VERSION 5.7 ;
  NOWIREEXTENSIONATPIN ON ;
  DIVIDERCHAR "/" ;
  BUSBITCHARS "[]" ;
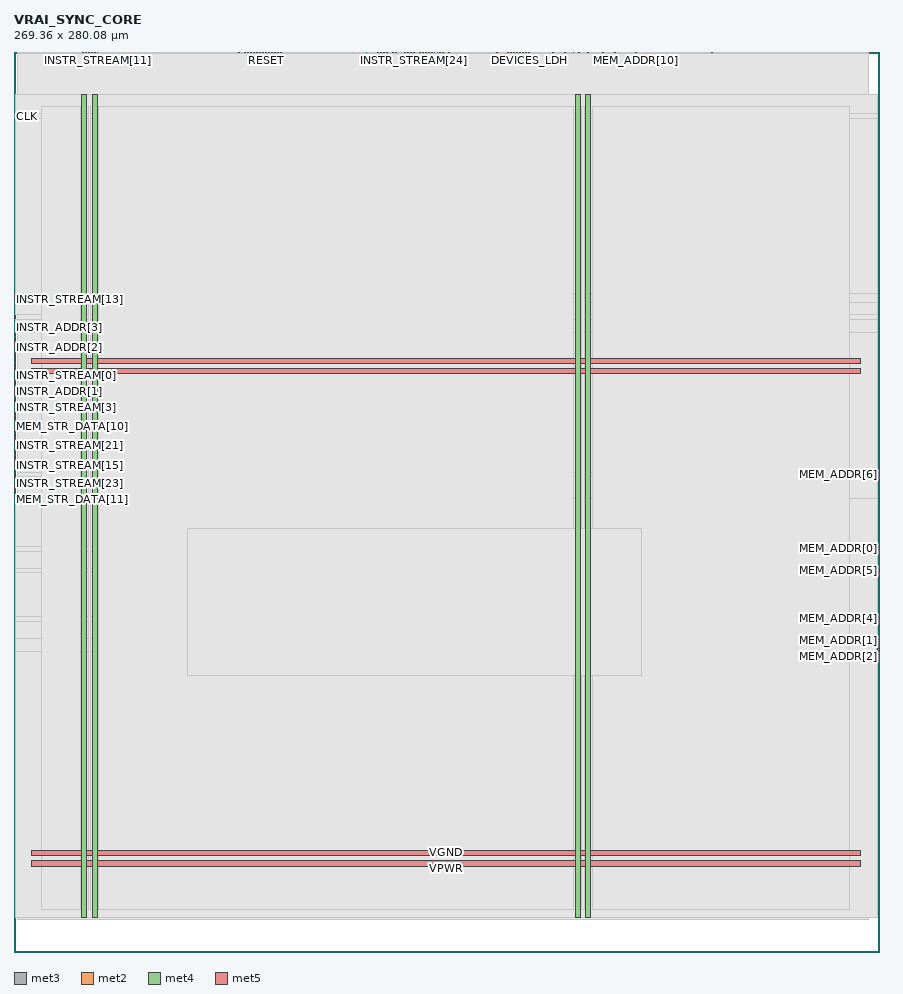
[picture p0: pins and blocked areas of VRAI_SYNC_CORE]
MACRO VRAI_SYNC_CORE
  CLASS BLOCK ;
  FOREIGN VRAI_SYNC_CORE ;
  ORIGIN 0.000 0.000 ;
  SIZE 269.360 BY 280.080 ;
  PIN CLK
    DIRECTION INPUT ;
    USE SIGNAL ;
    ANTENNAGATEAREA 0.852000 ;
    PORT
      LAYER met3 ;
        RECT 0.000 259.800 0.600 260.400 ;
    END
  END CLK
  PIN DEVICES_LDH
    DIRECTION OUTPUT ;
    USE SIGNAL ;
    ANTENNADIFFAREA 0.702900 ;
    PORT
      LAYER met2 ;
        RECT 160.170 279.800 160.450 280.080 ;
    END
  END DEVICES_LDH
  PIN DEVICES_LDW
    DIRECTION OUTPUT ;
    USE SIGNAL ;
    ANTENNADIFFAREA 0.702900 ;
    PORT
      LAYER met2 ;
        RECT 156.490 279.800 156.770 280.080 ;
    END
  END DEVICES_LDW
  PIN DEVICES_STRH
    DIRECTION OUTPUT ;
    USE SIGNAL ;
    ANTENNADIFFAREA 0.702900 ;
    PORT
      LAYER met2 ;
        RECT 158.330 279.800 158.610 280.080 ;
    END
  END DEVICES_STRH
  PIN DEVICES_STRW
    DIRECTION OUTPUT ;
    USE SIGNAL ;
    ANTENNADIFFAREA 0.702900 ;
    PORT
      LAYER met2 ;
        RECT 150.050 279.800 150.330 280.080 ;
    END
  END DEVICES_STRW
  PIN EX_HALT
    DIRECTION OUTPUT ;
    USE SIGNAL ;
    ANTENNADIFFAREA 0.702900 ;
    PORT
      LAYER met2 ;
        RECT 81.970 279.800 82.250 280.080 ;
    END
  END EX_HALT
  PIN INSTR_ADDR[0]
    DIRECTION OUTPUT ;
    USE SIGNAL ;
    ANTENNADIFFAREA 0.702900 ;
    PORT
      LAYER met3 ;
        RECT 0.000 178.200 0.600 178.800 ;
    END
  END INSTR_ADDR[0]
  PIN INSTR_ADDR[10]
    DIRECTION OUTPUT ;
    USE SIGNAL ;
    ANTENNADIFFAREA 0.702900 ;
    PORT
      LAYER met2 ;
        RECT 75.530 279.800 75.810 280.080 ;
    END
  END INSTR_ADDR[10]
  PIN INSTR_ADDR[11]
    DIRECTION OUTPUT ;
    USE SIGNAL ;
    ANTENNADIFFAREA 0.702900 ;
    PORT
      LAYER met2 ;
        RECT 77.370 279.800 77.650 280.080 ;
    END
  END INSTR_ADDR[11]
  PIN INSTR_ADDR[12]
    DIRECTION OUTPUT ;
    USE SIGNAL ;
    ANTENNADIFFAREA 0.702900 ;
    PORT
      LAYER met2 ;
        RECT 74.610 279.800 74.890 280.080 ;
    END
  END INSTR_ADDR[12]
  PIN INSTR_ADDR[13]
    DIRECTION OUTPUT ;
    USE SIGNAL ;
    ANTENNADIFFAREA 0.702900 ;
    PORT
      LAYER met2 ;
        RECT 81.050 279.800 81.330 280.080 ;
    END
  END INSTR_ADDR[13]
  PIN INSTR_ADDR[14]
    DIRECTION OUTPUT ;
    USE SIGNAL ;
    ANTENNADIFFAREA 0.702900 ;
    PORT
      LAYER met2 ;
        RECT 80.130 279.800 80.410 280.080 ;
    END
  END INSTR_ADDR[14]
  PIN INSTR_ADDR[15]
    DIRECTION OUTPUT ;
    USE SIGNAL ;
    ANTENNADIFFAREA 0.702900 ;
    PORT
      LAYER met2 ;
        RECT 79.210 279.800 79.490 280.080 ;
    END
  END INSTR_ADDR[15]
  PIN INSTR_ADDR[1]
    DIRECTION OUTPUT ;
    USE SIGNAL ;
    ANTENNADIFFAREA 0.702900 ;
    PORT
      LAYER met3 ;
        RECT 0.000 174.120 0.600 174.720 ;
    END
  END INSTR_ADDR[1]
  PIN INSTR_ADDR[2]
    DIRECTION OUTPUT ;
    USE SIGNAL ;
    ANTENNADIFFAREA 0.702900 ;
    PORT
      LAYER met3 ;
        RECT 0.000 187.720 0.600 188.320 ;
    END
  END INSTR_ADDR[2]
  PIN INSTR_ADDR[3]
    DIRECTION OUTPUT ;
    USE SIGNAL ;
    ANTENNADIFFAREA 0.702900 ;
    PORT
      LAYER met3 ;
        RECT 0.000 191.800 0.600 192.400 ;
    END
  END INSTR_ADDR[3]
  PIN INSTR_ADDR[4]
    DIRECTION OUTPUT ;
    USE SIGNAL ;
    ANTENNADIFFAREA 0.702900 ;
    PORT
      LAYER met3 ;
        RECT 0.000 189.080 0.600 189.680 ;
    END
  END INSTR_ADDR[4]
  PIN INSTR_ADDR[5]
    DIRECTION OUTPUT ;
    USE SIGNAL ;
    ANTENNADIFFAREA 0.702900 ;
    PORT
      LAYER met2 ;
        RECT 70.010 279.800 70.290 280.080 ;
    END
  END INSTR_ADDR[5]
  PIN INSTR_ADDR[6]
    DIRECTION OUTPUT ;
    USE SIGNAL ;
    ANTENNADIFFAREA 0.702900 ;
    PORT
      LAYER met2 ;
        RECT 76.450 279.800 76.730 280.080 ;
    END
  END INSTR_ADDR[6]
  PIN INSTR_ADDR[7]
    DIRECTION OUTPUT ;
    USE SIGNAL ;
    ANTENNADIFFAREA 0.702900 ;
    PORT
      LAYER met2 ;
        RECT 73.690 279.800 73.970 280.080 ;
    END
  END INSTR_ADDR[7]
  PIN INSTR_ADDR[8]
    DIRECTION OUTPUT ;
    USE SIGNAL ;
    ANTENNADIFFAREA 0.702900 ;
    PORT
      LAYER met2 ;
        RECT 72.770 279.800 73.050 280.080 ;
    END
  END INSTR_ADDR[8]
  PIN INSTR_ADDR[9]
    DIRECTION OUTPUT ;
    USE SIGNAL ;
    ANTENNADIFFAREA 0.702900 ;
    PORT
      LAYER met2 ;
        RECT 71.850 279.800 72.130 280.080 ;
    END
  END INSTR_ADDR[9]
  PIN INSTR_STREAM[0]
    DIRECTION INPUT ;
    USE SIGNAL ;
    ANTENNAGATEAREA 0.213000 ;
    PORT
      LAYER met3 ;
        RECT 0.000 176.840 0.600 177.440 ;
    END
  END INSTR_STREAM[0]
  PIN INSTR_STREAM[10]
    DIRECTION INPUT ;
    USE SIGNAL ;
    ANTENNAGATEAREA 0.213000 ;
    PORT
      LAYER met2 ;
        RECT 23.090 279.800 23.370 280.080 ;
    END
  END INSTR_STREAM[10]
  PIN INSTR_STREAM[11]
    DIRECTION INPUT ;
    USE SIGNAL ;
    ANTENNAGATEAREA 0.213000 ;
    PORT
      LAYER met2 ;
        RECT 25.850 279.800 26.130 280.080 ;
    END
  END INSTR_STREAM[11]
  PIN INSTR_STREAM[12]
    DIRECTION INPUT ;
    USE SIGNAL ;
    ANTENNAGATEAREA 0.213000 ;
    PORT
      LAYER met2 ;
        RECT 24.010 279.800 24.290 280.080 ;
    END
  END INSTR_STREAM[12]
  PIN INSTR_STREAM[13]
    DIRECTION INPUT ;
    USE SIGNAL ;
    ANTENNAGATEAREA 0.213000 ;
    PORT
      LAYER met3 ;
        RECT 0.000 202.680 0.600 203.280 ;
    END
  END INSTR_STREAM[13]
  PIN INSTR_STREAM[14]
    DIRECTION INPUT ;
    USE SIGNAL ;
    ANTENNAGATEAREA 0.213000 ;
    PORT
      LAYER met3 ;
        RECT 0.000 141.480 0.600 142.080 ;
    END
  END INSTR_STREAM[14]
  PIN INSTR_STREAM[15]
    DIRECTION INPUT ;
    USE SIGNAL ;
    ANTENNAGATEAREA 0.213000 ;
    PORT
      LAYER met3 ;
        RECT 0.000 151.000 0.600 151.600 ;
    END
  END INSTR_STREAM[15]
  PIN INSTR_STREAM[16]
    DIRECTION INPUT ;
    USE SIGNAL ;
    ANTENNAGATEAREA 0.213000 ;
    PORT
      LAYER met3 ;
        RECT 0.000 182.280 0.600 182.880 ;
    END
  END INSTR_STREAM[16]
  PIN INSTR_STREAM[17]
    DIRECTION INPUT ;
    USE SIGNAL ;
    ANTENNAGATEAREA 0.213000 ;
    PORT
      LAYER met3 ;
        RECT 0.000 172.760 0.600 173.360 ;
    END
  END INSTR_STREAM[17]
  PIN INSTR_STREAM[18]
    DIRECTION INPUT ;
    USE SIGNAL ;
    ANTENNAGATEAREA 0.213000 ;
    PORT
      LAYER met3 ;
        RECT 0.000 190.440 0.600 191.040 ;
    END
  END INSTR_STREAM[18]
  PIN INSTR_STREAM[19]
    DIRECTION INPUT ;
    USE SIGNAL ;
    ANTENNAGATEAREA 0.213000 ;
    PORT
      LAYER met3 ;
        RECT 0.000 186.360 0.600 186.960 ;
    END
  END INSTR_STREAM[19]
  PIN INSTR_STREAM[1]
    DIRECTION INPUT ;
    USE SIGNAL ;
    ANTENNAGATEAREA 0.213000 ;
    PORT
      LAYER met3 ;
        RECT 0.000 183.640 0.600 184.240 ;
    END
  END INSTR_STREAM[1]
  PIN INSTR_STREAM[20]
    DIRECTION INPUT ;
    USE SIGNAL ;
    ANTENNAGATEAREA 0.213000 ;
    PORT
      LAYER met3 ;
        RECT 0.000 146.920 0.600 147.520 ;
    END
  END INSTR_STREAM[20]
  PIN INSTR_STREAM[21]
    DIRECTION INPUT ;
    USE SIGNAL ;
    ANTENNAGATEAREA 0.213000 ;
    PORT
      LAYER met3 ;
        RECT 0.000 155.080 0.600 155.680 ;
    END
  END INSTR_STREAM[21]
  PIN INSTR_STREAM[22]
    DIRECTION INPUT ;
    USE SIGNAL ;
    ANTENNAGATEAREA 0.213000 ;
    PORT
      LAYER met3 ;
        RECT 0.000 156.440 0.600 157.040 ;
    END
  END INSTR_STREAM[22]
  PIN INSTR_STREAM[23]
    DIRECTION INPUT ;
    USE SIGNAL ;
    ANTENNAGATEAREA 0.213000 ;
    PORT
      LAYER met3 ;
        RECT 0.000 145.560 0.600 146.160 ;
    END
  END INSTR_STREAM[23]
  PIN INSTR_STREAM[24]
    DIRECTION INPUT ;
    USE SIGNAL ;
    ANTENNAGATEAREA 0.213000 ;
    PORT
      LAYER met2 ;
        RECT 124.290 279.800 124.570 280.080 ;
    END
  END INSTR_STREAM[24]
  PIN INSTR_STREAM[25]
    DIRECTION INPUT ;
    USE SIGNAL ;
    ANTENNAGATEAREA 0.213000 ;
    PORT
      LAYER met2 ;
        RECT 121.530 279.800 121.810 280.080 ;
    END
  END INSTR_STREAM[25]
  PIN INSTR_STREAM[26]
    DIRECTION INPUT ;
    USE SIGNAL ;
    ANTENNAGATEAREA 0.213000 ;
    PORT
      LAYER met2 ;
        RECT 122.450 279.800 122.730 280.080 ;
    END
  END INSTR_STREAM[26]
  PIN INSTR_STREAM[27]
    DIRECTION INPUT ;
    USE SIGNAL ;
    ANTENNAGATEAREA 0.213000 ;
    PORT
      LAYER met2 ;
        RECT 123.370 279.800 123.650 280.080 ;
    END
  END INSTR_STREAM[27]
  PIN INSTR_STREAM[28]
    DIRECTION INPUT ;
    USE SIGNAL ;
    ANTENNAGATEAREA 0.213000 ;
    PORT
      LAYER met2 ;
        RECT 82.890 279.800 83.170 280.080 ;
    END
  END INSTR_STREAM[28]
  PIN INSTR_STREAM[29]
    DIRECTION INPUT ;
    USE SIGNAL ;
    ANTENNAGATEAREA 0.213000 ;
    PORT
      LAYER met2 ;
        RECT 117.850 279.800 118.130 280.080 ;
    END
  END INSTR_STREAM[29]
  PIN INSTR_STREAM[2]
    DIRECTION INPUT ;
    USE SIGNAL ;
    ANTENNAGATEAREA 0.213000 ;
    PORT
      LAYER met3 ;
        RECT 0.000 185.000 0.600 185.600 ;
    END
  END INSTR_STREAM[2]
  PIN INSTR_STREAM[30]
    DIRECTION INPUT ;
    USE SIGNAL ;
    ANTENNAGATEAREA 0.213000 ;
    PORT
      LAYER met2 ;
        RECT 116.010 279.800 116.290 280.080 ;
    END
  END INSTR_STREAM[30]
  PIN INSTR_STREAM[31]
    DIRECTION INPUT ;
    USE SIGNAL ;
    ANTENNAGATEAREA 0.213000 ;
    PORT
      LAYER met2 ;
        RECT 109.570 279.800 109.850 280.080 ;
    END
  END INSTR_STREAM[31]
  PIN INSTR_STREAM[3]
    DIRECTION INPUT ;
    USE SIGNAL ;
    ANTENNAGATEAREA 0.213000 ;
    PORT
      LAYER met3 ;
        RECT 0.000 171.400 0.600 172.000 ;
    END
  END INSTR_STREAM[3]
  PIN INSTR_STREAM[4]
    DIRECTION INPUT ;
    USE SIGNAL ;
    ANTENNAGATEAREA 0.213000 ;
    PORT
      LAYER met3 ;
        RECT 0.000 170.040 0.600 170.640 ;
    END
  END INSTR_STREAM[4]
  PIN INSTR_STREAM[5]
    DIRECTION INPUT ;
    USE SIGNAL ;
    ANTENNAGATEAREA 0.213000 ;
    PORT
      LAYER met3 ;
        RECT 0.000 197.240 0.600 197.840 ;
    END
  END INSTR_STREAM[5]
  PIN INSTR_STREAM[6]
    DIRECTION INPUT ;
    USE SIGNAL ;
    ANTENNAGATEAREA 0.213000 ;
    PORT
      LAYER met3 ;
        RECT 0.000 204.040 0.600 204.640 ;
    END
  END INSTR_STREAM[6]
  PIN INSTR_STREAM[7]
    DIRECTION INPUT ;
    USE SIGNAL ;
    ANTENNAGATEAREA 0.213000 ;
    PORT
      LAYER met2 ;
        RECT 24.930 279.800 25.210 280.080 ;
    END
  END INSTR_STREAM[7]
  PIN INSTR_STREAM[8]
    DIRECTION INPUT ;
    USE SIGNAL ;
    ANTENNAGATEAREA 0.213000 ;
    PORT
      LAYER met2 ;
        RECT 21.250 279.800 21.530 280.080 ;
    END
  END INSTR_STREAM[8]
  PIN INSTR_STREAM[9]
    DIRECTION INPUT ;
    USE SIGNAL ;
    ANTENNAGATEAREA 0.213000 ;
    PORT
      LAYER met2 ;
        RECT 22.170 279.800 22.450 280.080 ;
    END
  END INSTR_STREAM[9]
  PIN INVALID_MEM
    DIRECTION OUTPUT ;
    USE SIGNAL ;
    ANTENNADIFFAREA 0.702900 ;
    PORT
      LAYER met2 ;
        RECT 171.210 279.800 171.490 280.080 ;
    END
  END INVALID_MEM
  PIN MAIN_LDH
    DIRECTION OUTPUT ;
    USE SIGNAL ;
    ANTENNADIFFAREA 0.702900 ;
    PORT
      LAYER met2 ;
        RECT 159.250 279.800 159.530 280.080 ;
    END
  END MAIN_LDH
  PIN MAIN_LDW
    DIRECTION OUTPUT ;
    USE SIGNAL ;
    ANTENNADIFFAREA 0.702900 ;
    PORT
      LAYER met2 ;
        RECT 155.570 279.800 155.850 280.080 ;
    END
  END MAIN_LDW
  PIN MAIN_STRH
    DIRECTION OUTPUT ;
    USE SIGNAL ;
    ANTENNADIFFAREA 0.702900 ;
    PORT
      LAYER met2 ;
        RECT 157.410 279.800 157.690 280.080 ;
    END
  END MAIN_STRH
  PIN MAIN_STRW
    DIRECTION OUTPUT ;
    USE SIGNAL ;
    ANTENNADIFFAREA 0.702900 ;
    PORT
      LAYER met2 ;
        RECT 154.650 279.800 154.930 280.080 ;
    END
  END MAIN_STRW
  PIN MEM_ADDR[0]
    DIRECTION OUTPUT ;
    USE SIGNAL ;
    ANTENNADIFFAREA 0.702900 ;
    PORT
      LAYER met3 ;
        RECT 268.760 125.160 269.360 125.760 ;
    END
  END MEM_ADDR[0]
  PIN MEM_ADDR[10]
    DIRECTION OUTPUT ;
    USE SIGNAL ;
    ANTENNADIFFAREA 0.702900 ;
    PORT
      LAYER met2 ;
        RECT 193.290 279.800 193.570 280.080 ;
    END
  END MEM_ADDR[10]
  PIN MEM_ADDR[11]
    DIRECTION OUTPUT ;
    USE SIGNAL ;
    ANTENNADIFFAREA 0.702900 ;
    PORT
      LAYER met2 ;
        RECT 183.170 279.800 183.450 280.080 ;
    END
  END MEM_ADDR[11]
  PIN MEM_ADDR[12]
    DIRECTION OUTPUT ;
    USE SIGNAL ;
    ANTENNADIFFAREA 0.702900 ;
    PORT
      LAYER met2 ;
        RECT 178.570 279.800 178.850 280.080 ;
    END
  END MEM_ADDR[12]
  PIN MEM_ADDR[13]
    DIRECTION OUTPUT ;
    USE SIGNAL ;
    ANTENNADIFFAREA 0.702900 ;
    PORT
      LAYER met2 ;
        RECT 175.810 279.800 176.090 280.080 ;
    END
  END MEM_ADDR[13]
  PIN MEM_ADDR[14]
    DIRECTION OUTPUT ;
    USE SIGNAL ;
    ANTENNADIFFAREA 0.702900 ;
    PORT
      LAYER met2 ;
        RECT 167.530 279.800 167.810 280.080 ;
    END
  END MEM_ADDR[14]
  PIN MEM_ADDR[15]
    DIRECTION OUTPUT ;
    USE SIGNAL ;
    ANTENNADIFFAREA 0.702900 ;
    PORT
      LAYER met2 ;
        RECT 153.730 279.800 154.010 280.080 ;
    END
  END MEM_ADDR[15]
  PIN MEM_ADDR[1]
    DIRECTION OUTPUT ;
    USE SIGNAL ;
    ANTENNADIFFAREA 0.702900 ;
    PORT
      LAYER met3 ;
        RECT 268.760 96.600 269.360 97.200 ;
    END
  END MEM_ADDR[1]
  PIN MEM_ADDR[2]
    DIRECTION OUTPUT ;
    USE SIGNAL ;
    ANTENNADIFFAREA 0.702900 ;
    PORT
      LAYER met3 ;
        RECT 268.760 93.880 269.360 94.480 ;
    END
  END MEM_ADDR[2]
  PIN MEM_ADDR[3]
    DIRECTION OUTPUT ;
    USE SIGNAL ;
    ANTENNADIFFAREA 0.702900 ;
    PORT
      LAYER met3 ;
        RECT 268.760 95.240 269.360 95.840 ;
    END
  END MEM_ADDR[3]
  PIN MEM_ADDR[4]
    DIRECTION OUTPUT ;
    USE SIGNAL ;
    ANTENNADIFFAREA 0.702900 ;
    PORT
      LAYER met3 ;
        RECT 268.760 103.400 269.360 104.000 ;
    END
  END MEM_ADDR[4]
  PIN MEM_ADDR[5]
    DIRECTION OUTPUT ;
    USE SIGNAL ;
    ANTENNADIFFAREA 0.702900 ;
    PORT
      LAYER met3 ;
        RECT 268.760 118.360 269.360 118.960 ;
    END
  END MEM_ADDR[5]
  PIN MEM_ADDR[6]
    DIRECTION OUTPUT ;
    USE SIGNAL ;
    ANTENNADIFFAREA 0.702900 ;
    PORT
      LAYER met3 ;
        RECT 268.760 148.280 269.360 148.880 ;
    END
  END MEM_ADDR[6]
  PIN MEM_ADDR[7]
    DIRECTION OUTPUT ;
    USE SIGNAL ;
    ANTENNADIFFAREA 0.702900 ;
    PORT
      LAYER met2 ;
        RECT 173.970 279.800 174.250 280.080 ;
    END
  END MEM_ADDR[7]
  PIN MEM_ADDR[8]
    DIRECTION OUTPUT ;
    USE SIGNAL ;
    ANTENNADIFFAREA 0.702900 ;
    PORT
      LAYER met2 ;
        RECT 186.850 279.800 187.130 280.080 ;
    END
  END MEM_ADDR[8]
  PIN MEM_ADDR[9]
    DIRECTION OUTPUT ;
    USE SIGNAL ;
    ANTENNADIFFAREA 0.702900 ;
    PORT
      LAYER met2 ;
        RECT 217.210 279.800 217.490 280.080 ;
    END
  END MEM_ADDR[9]
  PIN MEM_LD_DATA[0]
    DIRECTION INPUT ;
    USE SIGNAL ;
    ANTENNAGATEAREA 0.213000 ;
    PORT
      LAYER met2 ;
        RECT 128.890 279.800 129.170 280.080 ;
    END
  END MEM_LD_DATA[0]
  PIN MEM_LD_DATA[10]
    DIRECTION INPUT ;
    USE SIGNAL ;
    ANTENNAGATEAREA 0.213000 ;
    PORT
      LAYER met2 ;
        RECT 132.570 279.800 132.850 280.080 ;
    END
  END MEM_LD_DATA[10]
  PIN MEM_LD_DATA[11]
    DIRECTION INPUT ;
    USE SIGNAL ;
    ANTENNAGATEAREA 0.213000 ;
    PORT
      LAYER met2 ;
        RECT 118.770 279.800 119.050 280.080 ;
    END
  END MEM_LD_DATA[11]
  PIN MEM_LD_DATA[12]
    DIRECTION INPUT ;
    USE SIGNAL ;
    ANTENNAGATEAREA 0.213000 ;
    PORT
      LAYER met2 ;
        RECT 135.330 279.800 135.610 280.080 ;
    END
  END MEM_LD_DATA[12]
  PIN MEM_LD_DATA[13]
    DIRECTION INPUT ;
    USE SIGNAL ;
    ANTENNAGATEAREA 0.213000 ;
    PORT
      LAYER met2 ;
        RECT 130.730 279.800 131.010 280.080 ;
    END
  END MEM_LD_DATA[13]
  PIN MEM_LD_DATA[14]
    DIRECTION INPUT ;
    USE SIGNAL ;
    ANTENNAGATEAREA 0.213000 ;
    PORT
      LAYER met2 ;
        RECT 131.650 279.800 131.930 280.080 ;
    END
  END MEM_LD_DATA[14]
  PIN MEM_LD_DATA[15]
    DIRECTION INPUT ;
    USE SIGNAL ;
    ANTENNAGATEAREA 0.213000 ;
    PORT
      LAYER met2 ;
        RECT 127.050 279.800 127.330 280.080 ;
    END
  END MEM_LD_DATA[15]
  PIN MEM_LD_DATA[1]
    DIRECTION INPUT ;
    USE SIGNAL ;
    ANTENNAGATEAREA 0.213000 ;
    PORT
      LAYER met2 ;
        RECT 129.810 279.800 130.090 280.080 ;
    END
  END MEM_LD_DATA[1]
  PIN MEM_LD_DATA[2]
    DIRECTION INPUT ;
    USE SIGNAL ;
    ANTENNAGATEAREA 0.213000 ;
    PORT
      LAYER met2 ;
        RECT 115.090 279.800 115.370 280.080 ;
    END
  END MEM_LD_DATA[2]
  PIN MEM_LD_DATA[3]
    DIRECTION INPUT ;
    USE SIGNAL ;
    ANTENNAGATEAREA 0.213000 ;
    PORT
      LAYER met2 ;
        RECT 127.970 279.800 128.250 280.080 ;
    END
  END MEM_LD_DATA[3]
  PIN MEM_LD_DATA[4]
    DIRECTION INPUT ;
    USE SIGNAL ;
    ANTENNAGATEAREA 0.213000 ;
    PORT
      LAYER met2 ;
        RECT 113.250 279.800 113.530 280.080 ;
    END
  END MEM_LD_DATA[4]
  PIN MEM_LD_DATA[5]
    DIRECTION INPUT ;
    USE SIGNAL ;
    ANTENNAGATEAREA 0.213000 ;
    PORT
      LAYER met3 ;
        RECT 0.000 180.920 0.600 181.520 ;
    END
  END MEM_LD_DATA[5]
  PIN MEM_LD_DATA[6]
    DIRECTION INPUT ;
    USE SIGNAL ;
    ANTENNAGATEAREA 0.213000 ;
    PORT
      LAYER met3 ;
        RECT 0.000 175.480 0.600 176.080 ;
    END
  END MEM_LD_DATA[6]
  PIN MEM_LD_DATA[7]
    DIRECTION INPUT ;
    USE SIGNAL ;
    ANTENNAGATEAREA 0.213000 ;
    PORT
      LAYER met2 ;
        RECT 114.170 279.800 114.450 280.080 ;
    END
  END MEM_LD_DATA[7]
  PIN MEM_LD_DATA[8]
    DIRECTION INPUT ;
    USE SIGNAL ;
    ANTENNAGATEAREA 0.213000 ;
    PORT
      LAYER met2 ;
        RECT 133.490 279.800 133.770 280.080 ;
    END
  END MEM_LD_DATA[8]
  PIN MEM_LD_DATA[9]
    DIRECTION INPUT ;
    USE SIGNAL ;
    ANTENNAGATEAREA 0.213000 ;
    PORT
      LAYER met2 ;
        RECT 126.130 279.800 126.410 280.080 ;
    END
  END MEM_LD_DATA[9]
  PIN MEM_STR_DATA[0]
    DIRECTION OUTPUT ;
    USE SIGNAL ;
    ANTENNADIFFAREA 0.702900 ;
    PORT
      LAYER met3 ;
        RECT 0.000 153.720 0.600 154.320 ;
    END
  END MEM_STR_DATA[0]
  PIN MEM_STR_DATA[10]
    DIRECTION OUTPUT ;
    USE SIGNAL ;
    ANTENNADIFFAREA 0.702900 ;
    PORT
      LAYER met3 ;
        RECT 0.000 163.240 0.600 163.840 ;
    END
  END MEM_STR_DATA[10]
  PIN MEM_STR_DATA[11]
    DIRECTION OUTPUT ;
    USE SIGNAL ;
    ANTENNADIFFAREA 0.702900 ;
    PORT
      LAYER met3 ;
        RECT 0.000 142.840 0.600 143.440 ;
    END
  END MEM_STR_DATA[11]
  PIN MEM_STR_DATA[12]
    DIRECTION OUTPUT ;
    USE SIGNAL ;
    ANTENNADIFFAREA 0.702900 ;
    PORT
      LAYER met3 ;
        RECT 0.000 157.800 0.600 158.400 ;
    END
  END MEM_STR_DATA[12]
  PIN MEM_STR_DATA[13]
    DIRECTION OUTPUT ;
    USE SIGNAL ;
    ANTENNADIFFAREA 0.702900 ;
    PORT
      LAYER met3 ;
        RECT 0.000 161.880 0.600 162.480 ;
    END
  END MEM_STR_DATA[13]
  PIN MEM_STR_DATA[14]
    DIRECTION OUTPUT ;
    USE SIGNAL ;
    ANTENNADIFFAREA 0.702900 ;
    PORT
      LAYER met3 ;
        RECT 0.000 159.160 0.600 159.760 ;
    END
  END MEM_STR_DATA[14]
  PIN MEM_STR_DATA[15]
    DIRECTION OUTPUT ;
    USE SIGNAL ;
    ANTENNADIFFAREA 0.702900 ;
    PORT
      LAYER met3 ;
        RECT 0.000 144.200 0.600 144.800 ;
    END
  END MEM_STR_DATA[15]
  PIN MEM_STR_DATA[1]
    DIRECTION OUTPUT ;
    USE SIGNAL ;
    ANTENNADIFFAREA 0.702900 ;
    PORT
      LAYER met3 ;
        RECT 0.000 148.280 0.600 148.880 ;
    END
  END MEM_STR_DATA[1]
  PIN MEM_STR_DATA[2]
    DIRECTION OUTPUT ;
    USE SIGNAL ;
    ANTENNADIFFAREA 0.702900 ;
    PORT
      LAYER met3 ;
        RECT 0.000 152.360 0.600 152.960 ;
    END
  END MEM_STR_DATA[2]
  PIN MEM_STR_DATA[3]
    DIRECTION OUTPUT ;
    USE SIGNAL ;
    ANTENNADIFFAREA 0.702900 ;
    PORT
      LAYER met3 ;
        RECT 0.000 165.960 0.600 166.560 ;
    END
  END MEM_STR_DATA[3]
  PIN MEM_STR_DATA[4]
    DIRECTION OUTPUT ;
    USE SIGNAL ;
    ANTENNADIFFAREA 0.702900 ;
    PORT
      LAYER met3 ;
        RECT 0.000 167.320 0.600 167.920 ;
    END
  END MEM_STR_DATA[4]
  PIN MEM_STR_DATA[5]
    DIRECTION OUTPUT ;
    USE SIGNAL ;
    ANTENNADIFFAREA 0.702900 ;
    PORT
      LAYER met3 ;
        RECT 0.000 164.600 0.600 165.200 ;
    END
  END MEM_STR_DATA[5]
  PIN MEM_STR_DATA[6]
    DIRECTION OUTPUT ;
    USE SIGNAL ;
    ANTENNADIFFAREA 0.702900 ;
    PORT
      LAYER met3 ;
        RECT 0.000 160.520 0.600 161.120 ;
    END
  END MEM_STR_DATA[6]
  PIN MEM_STR_DATA[7]
    DIRECTION OUTPUT ;
    USE SIGNAL ;
    ANTENNADIFFAREA 0.702900 ;
    PORT
      LAYER met3 ;
        RECT 0.000 168.680 0.600 169.280 ;
    END
  END MEM_STR_DATA[7]
  PIN MEM_STR_DATA[8]
    DIRECTION OUTPUT ;
    USE SIGNAL ;
    ANTENNADIFFAREA 0.702900 ;
    PORT
      LAYER met3 ;
        RECT 0.000 149.640 0.600 150.240 ;
    END
  END MEM_STR_DATA[8]
  PIN MEM_STR_DATA[9]
    DIRECTION OUTPUT ;
    USE SIGNAL ;
    ANTENNADIFFAREA 0.702900 ;
    PORT
      LAYER met3 ;
        RECT 0.000 179.560 0.600 180.160 ;
    END
  END MEM_STR_DATA[9]
  PIN RESET
    DIRECTION INPUT ;
    USE SIGNAL ;
    ANTENNAGATEAREA 0.247500 ;
    PORT
      LAYER met2 ;
        RECT 78.290 279.800 78.570 280.080 ;
    END
  END RESET
  PIN VGND
    DIRECTION INOUT ;
    USE GROUND ;
    PORT
      LAYER met4 ;
        RECT 24.340 10.640 25.940 266.800 ;
    END
    PORT
      LAYER met4 ;
        RECT 177.940 10.640 179.540 266.800 ;
    END
    PORT
      LAYER met5 ;
        RECT 5.520 30.030 263.580 31.630 ;
    END
    PORT
      LAYER met5 ;
        RECT 5.520 183.210 263.580 184.810 ;
    END
  END VGND
  PIN VPWR
    DIRECTION INOUT ;
    USE POWER ;
    PORT
      LAYER met4 ;
        RECT 21.040 10.640 22.640 266.800 ;
    END
    PORT
      LAYER met4 ;
        RECT 174.640 10.640 176.240 266.800 ;
    END
    PORT
      LAYER met5 ;
        RECT 5.520 26.730 263.580 28.330 ;
    END
    PORT
      LAYER met5 ;
        RECT 5.520 179.910 263.580 181.510 ;
    END
  END VPWR
  OBS
      LAYER nwell ;
        RECT 5.330 10.795 263.770 266.645 ;
      LAYER li1 ;
        RECT 5.520 10.795 263.580 266.645 ;
      LAYER met1 ;
        RECT 0.990 10.240 265.810 267.200 ;
      LAYER met2 ;
        RECT 1.010 279.520 20.970 279.800 ;
        RECT 21.810 279.520 21.890 279.800 ;
        RECT 22.730 279.520 22.810 279.800 ;
        RECT 23.650 279.520 23.730 279.800 ;
        RECT 24.570 279.520 24.650 279.800 ;
        RECT 25.490 279.520 25.570 279.800 ;
        RECT 26.410 279.520 69.730 279.800 ;
        RECT 70.570 279.520 71.570 279.800 ;
        RECT 72.410 279.520 72.490 279.800 ;
        RECT 73.330 279.520 73.410 279.800 ;
        RECT 74.250 279.520 74.330 279.800 ;
        RECT 75.170 279.520 75.250 279.800 ;
        RECT 76.090 279.520 76.170 279.800 ;
        RECT 77.010 279.520 77.090 279.800 ;
        RECT 77.930 279.520 78.010 279.800 ;
        RECT 78.850 279.520 78.930 279.800 ;
        RECT 79.770 279.520 79.850 279.800 ;
        RECT 80.690 279.520 80.770 279.800 ;
        RECT 81.610 279.520 81.690 279.800 ;
        RECT 82.530 279.520 82.610 279.800 ;
        RECT 83.450 279.520 109.290 279.800 ;
        RECT 110.130 279.520 112.970 279.800 ;
        RECT 113.810 279.520 113.890 279.800 ;
        RECT 114.730 279.520 114.810 279.800 ;
        RECT 115.650 279.520 115.730 279.800 ;
        RECT 116.570 279.520 117.570 279.800 ;
        RECT 118.410 279.520 118.490 279.800 ;
        RECT 119.330 279.520 121.250 279.800 ;
        RECT 122.090 279.520 122.170 279.800 ;
        RECT 123.010 279.520 123.090 279.800 ;
        RECT 123.930 279.520 124.010 279.800 ;
        RECT 124.850 279.520 125.850 279.800 ;
        RECT 126.690 279.520 126.770 279.800 ;
        RECT 127.610 279.520 127.690 279.800 ;
        RECT 128.530 279.520 128.610 279.800 ;
        RECT 129.450 279.520 129.530 279.800 ;
        RECT 130.370 279.520 130.450 279.800 ;
        RECT 131.290 279.520 131.370 279.800 ;
        RECT 132.210 279.520 132.290 279.800 ;
        RECT 133.130 279.520 133.210 279.800 ;
        RECT 134.050 279.520 135.050 279.800 ;
        RECT 135.890 279.520 149.770 279.800 ;
        RECT 150.610 279.520 153.450 279.800 ;
        RECT 154.290 279.520 154.370 279.800 ;
        RECT 155.210 279.520 155.290 279.800 ;
        RECT 156.130 279.520 156.210 279.800 ;
        RECT 157.050 279.520 157.130 279.800 ;
        RECT 157.970 279.520 158.050 279.800 ;
        RECT 158.890 279.520 158.970 279.800 ;
        RECT 159.810 279.520 159.890 279.800 ;
        RECT 160.730 279.520 167.250 279.800 ;
        RECT 168.090 279.520 170.930 279.800 ;
        RECT 171.770 279.520 173.690 279.800 ;
        RECT 174.530 279.520 175.530 279.800 ;
        RECT 176.370 279.520 178.290 279.800 ;
        RECT 179.130 279.520 182.890 279.800 ;
        RECT 183.730 279.520 186.570 279.800 ;
        RECT 187.410 279.520 193.010 279.800 ;
        RECT 193.850 279.520 216.930 279.800 ;
        RECT 217.770 279.520 265.790 279.800 ;
        RECT 1.010 10.210 265.790 279.520 ;
      LAYER met3 ;
        RECT 0.600 260.800 268.760 266.725 ;
        RECT 1.000 259.400 268.760 260.800 ;
        RECT 0.600 205.040 268.760 259.400 ;
        RECT 1.000 202.280 268.760 205.040 ;
        RECT 0.600 198.240 268.760 202.280 ;
        RECT 1.000 196.840 268.760 198.240 ;
        RECT 0.600 192.800 268.760 196.840 ;
        RECT 1.000 149.280 268.760 192.800 ;
        RECT 1.000 147.880 268.360 149.280 ;
        RECT 1.000 141.080 268.760 147.880 ;
        RECT 0.600 126.160 268.760 141.080 ;
        RECT 0.600 124.760 268.360 126.160 ;
        RECT 0.600 119.360 268.760 124.760 ;
        RECT 0.600 117.960 268.360 119.360 ;
        RECT 0.600 104.400 268.760 117.960 ;
        RECT 0.600 103.000 268.360 104.400 ;
        RECT 0.600 97.600 268.760 103.000 ;
        RECT 0.600 93.480 268.360 97.600 ;
        RECT 0.600 10.715 268.760 93.480 ;
      LAYER met4 ;
        RECT 8.575 13.095 20.640 262.985 ;
        RECT 23.040 13.095 23.940 262.985 ;
        RECT 26.340 13.095 174.240 262.985 ;
        RECT 176.640 13.095 177.540 262.985 ;
        RECT 179.940 13.095 260.065 262.985 ;
      LAYER met5 ;
        RECT 53.940 85.900 195.380 131.700 ;
  END
END VRAI_SYNC_CORE
END LIBRARY

